VERSION 5.8 ;
BUSBITCHARS "[]" ;
DIVIDERCHAR "/" ;
UNITS
    DATABASE MICRONS 1000 ;
END UNITS

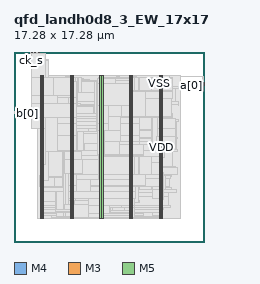
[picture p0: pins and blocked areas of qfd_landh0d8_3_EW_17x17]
MACRO qfd_landh0d8_3_EW_17x17
  FOREIGN qfd_landh0d8_3_EW_17x17 0 0 ;
  CLASS BLOCK ;
  SIZE 17.28 BY 17.28 ;
  PIN a[0]
    DIRECTION INPUT ;
    USE SIGNAL ;
    PORT
      LAYER M4 ;
        RECT  17.196 14.256 17.28 14.28 ;
    END
  END a[0]
  PIN a[1]
    DIRECTION INPUT ;
    USE SIGNAL ;
    PORT
      LAYER M4 ;
        RECT  17.196 14.352 17.28 14.376 ;
    END
  END a[1]
  PIN a[2]
    DIRECTION INPUT ;
    USE SIGNAL ;
    PORT
      LAYER M4 ;
        RECT  17.196 14.448 17.28 14.472 ;
    END
  END a[2]
  PIN b[0]
    DIRECTION OUTPUT ;
    USE SIGNAL ;
    PORT
      LAYER M4 ;
        RECT  0 11.664 0.084 11.688 ;
    END
  END b[0]
  PIN b[1]
    DIRECTION OUTPUT ;
    USE SIGNAL ;
    PORT
      LAYER M4 ;
        RECT  0 11.76 0.084 11.784 ;
    END
  END b[1]
  PIN b[2]
    DIRECTION OUTPUT ;
    USE SIGNAL ;
    PORT
      LAYER M4 ;
        RECT  0 11.856 0.084 11.88 ;
    END
  END b[2]
  PIN ck
    DIRECTION INPUT ;
    USE SIGNAL ;
    PORT
      LAYER M3 ;
        RECT  1.548 17.243 1.566 17.28 ;
    END
  END ck
  PIN ck_s
    DIRECTION INPUT ;
    USE SIGNAL ;
    PORT
      LAYER M3 ;
        RECT  1.62 17.243 1.638 17.28 ;
    END
  END ck_s
  PIN en
    DIRECTION INPUT ;
    USE SIGNAL ;
    PORT
      LAYER M3 ;
        RECT  1.692 17.243 1.71 17.28 ;
    END
  END en
  PIN fault
    DIRECTION OUTPUT ;
    USE SIGNAL ;
    PORT
      LAYER M3 ;
        RECT  1.764 17.243 1.782 17.28 ;
    END
  END fault
  PIN k0
    DIRECTION INPUT ;
    USE SIGNAL ;
    PORT
      LAYER M3 ;
        RECT  1.836 17.243 1.854 17.28 ;
    END
  END k0
  PIN k1
    DIRECTION INPUT ;
    USE SIGNAL ;
    PORT
      LAYER M3 ;
        RECT  1.908 17.243 1.926 17.28 ;
    END
  END k1
  PIN k2
    DIRECTION INPUT ;
    USE SIGNAL ;
    PORT
      LAYER M3 ;
        RECT  1.98 17.243 1.998 17.28 ;
    END
  END k2
  PIN k3
    DIRECTION INPUT ;
    USE SIGNAL ;
    PORT
      LAYER M3 ;
        RECT  2.052 17.243 2.07 17.28 ;
    END
  END k3
  PIN rs
    DIRECTION INPUT ;
    USE SIGNAL ;
    PORT
      LAYER M3 ;
        RECT  2.124 17.243 2.142 17.28 ;
    END
  END rs
  PIN tie_hi
    DIRECTION OUTPUT ;
    USE SIGNAL ;
    PORT
      LAYER M3 ;
        RECT  2.196 17.243 2.214 17.28 ;
    END
  END tie_hi
  PIN tie_lo
    DIRECTION OUTPUT ;
    USE SIGNAL ;
    PORT
      LAYER M3 ;
        RECT  2.268 17.243 2.286 17.28 ;
    END
  END tie_lo
  PIN VDD
    DIRECTION INOUT ;
    USE POWER ;
    PORT
      LAYER M5 ;
        RECT  13.392 2.151 13.512 15.129 ;
        RECT  10.692 2.151 10.812 15.129 ;
        RECT  7.992 2.151 8.112 15.129 ;
        RECT  5.292 2.151 5.412 15.129 ;
        RECT  2.592 2.151 2.712 15.129 ;
    END
  END VDD
  PIN VSS
    DIRECTION INOUT ;
    USE GROUND ;
    PORT
      LAYER M5 ;
        RECT  13.2 2.137 13.32 15.143 ;
        RECT  10.5 2.137 10.62 15.143 ;
        RECT  7.8 2.137 7.92 15.143 ;
        RECT  5.1 2.137 5.22 15.143 ;
        RECT  2.4 2.137 2.52 15.143 ;
    END
  END VSS
  # OT_OBS_CLOSED layer=M5 d_um=1.536 added=34
  OBS
    LAYER RVTN ;
     RECT  2.16 2.16 15.12 2.295 ;
     RECT  2.16 2.565 15.12 2.835 ;
     RECT  2.16 3.105 15.12 3.375 ;
     RECT  2.16 3.645 15.12 3.915 ;
     RECT  2.16 4.185 15.12 4.455 ;
     RECT  2.16 4.725 15.12 4.995 ;
     RECT  2.16 5.265 15.12 5.535 ;
     RECT  2.16 5.805 15.12 6.075 ;
     RECT  2.16 6.345 15.12 6.615 ;
     RECT  2.16 6.885 15.12 7.155 ;
     RECT  2.16 7.425 15.12 7.695 ;
     RECT  2.16 7.965 15.12 8.235 ;
     RECT  2.16 8.505 15.12 8.775 ;
     RECT  2.16 9.045 15.12 9.315 ;
     RECT  2.16 9.585 15.12 9.855 ;
     RECT  2.16 10.125 15.12 10.395 ;
     RECT  2.16 10.665 15.12 10.935 ;
     RECT  2.16 11.205 15.12 11.475 ;
     RECT  2.16 11.745 15.12 12.015 ;
     RECT  2.16 12.285 15.12 12.555 ;
     RECT  2.16 12.825 15.12 13.095 ;
     RECT  2.16 13.365 15.12 13.635 ;
     RECT  2.16 13.905 15.12 14.175 ;
     RECT  2.16 14.445 15.12 14.715 ;
     RECT  2.16 14.985 15.12 15.12 ;
    LAYER RVTP ;
     RECT  2.16 2.295 15.12 2.565 ;
     RECT  2.16 2.835 15.12 3.105 ;
     RECT  2.16 3.375 15.12 3.645 ;
     RECT  2.16 3.915 15.12 4.185 ;
     RECT  2.16 4.455 15.12 4.725 ;
     RECT  2.16 4.995 15.12 5.265 ;
     RECT  2.16 5.535 15.12 5.805 ;
     RECT  2.16 6.075 15.12 6.345 ;
     RECT  2.16 6.615 15.12 6.885 ;
     RECT  2.16 7.155 15.12 7.425 ;
     RECT  2.16 7.695 15.12 7.965 ;
     RECT  2.16 8.235 15.12 8.505 ;
     RECT  2.16 8.775 15.12 9.045 ;
     RECT  2.16 9.315 15.12 9.585 ;
     RECT  2.16 9.855 15.12 10.125 ;
     RECT  2.16 10.395 15.12 10.665 ;
     RECT  2.16 10.935 15.12 11.205 ;
     RECT  2.16 11.475 15.12 11.745 ;
     RECT  2.16 12.015 15.12 12.285 ;
     RECT  2.16 12.555 15.12 12.825 ;
     RECT  2.16 13.095 15.12 13.365 ;
     RECT  2.16 13.635 15.12 13.905 ;
     RECT  2.16 14.175 15.12 14.445 ;
     RECT  2.16 14.715 15.12 14.985 ;
    LAYER M1 ;
     RECT  2.16 2.151 15.12 15.129 ;
    LAYER M2 ;
     RECT  1.471 17.19 1.571 17.208 ;
     RECT  1.831 13.986 2.047 14.004 ;
     RECT  1.903 12.366 2.16 12.384 ;
     RECT  2.047 13.986 2.16 14.544 ;
     RECT  1.687 16.542 2.867 16.632 ;
     RECT  2.867 16.614 3.119 16.632 ;
     RECT  2.16 2.151 15.12 15.129 ;
     RECT  15.12 14.184 16.547 14.238 ;
     RECT  16.547 14.22 16.619 14.238 ;
     RECT  15.12 15.03 17.195 15.048 ;
    LAYER M3 ;
     RECT  7.815 2.143 7.905 2.191 ;
     RECT  5.115 2.143 5.205 2.227 ;
     RECT  8.64 2.191 8.658 2.227 ;
     RECT  10.515 2.143 10.605 2.227 ;
     RECT  13.215 2.143 13.305 2.227 ;
     RECT  6.3 2.227 6.318 2.251 ;
     RECT  7.668 2.191 7.905 2.251 ;
     RECT  6.3 2.251 7.905 2.263 ;
     RECT  8.64 2.227 9.378 2.263 ;
     RECT  10.515 2.227 10.962 2.263 ;
     RECT  6.3 2.263 10.962 2.371 ;
     RECT  11.772 2.251 11.79 2.371 ;
     RECT  2.415 2.143 2.505 2.413 ;
     RECT  3.384 2.227 5.205 2.413 ;
     RECT  12.564 2.227 13.305 2.413 ;
     RECT  2.415 2.413 5.397 2.605 ;
     RECT  6.3 2.371 11.79 2.605 ;
     RECT  2.415 2.605 11.79 2.641 ;
     RECT  12.564 2.413 13.497 2.641 ;
     RECT  2.415 2.641 13.497 2.911 ;
     RECT  2.415 2.911 13.554 3.145 ;
     RECT  2.415 3.145 14.202 3.299 ;
     RECT  2.415 3.299 14.094 4.145 ;
     RECT  10.008 4.145 14.094 4.531 ;
     RECT  10.008 4.531 14.814 4.757 ;
     RECT  10.008 4.757 14.31 4.919 ;
     RECT  2.415 4.145 9.09 4.927 ;
     RECT  10.008 4.919 14.202 4.927 ;
     RECT  2.415 4.927 14.202 4.955 ;
     RECT  2.415 4.955 14.166 5.035 ;
     RECT  2.34 5.035 14.166 5.063 ;
     RECT  4.392 5.063 14.166 5.737 ;
     RECT  4.392 5.737 14.202 5.773 ;
     RECT  2.34 5.063 3.654 5.845 ;
     RECT  4.392 5.773 14.238 5.845 ;
     RECT  2.34 5.845 14.238 5.995 ;
     RECT  2.34 5.995 14.346 6.077 ;
     RECT  2.415 6.077 14.346 6.115 ;
     RECT  2.415 6.115 14.85 6.809 ;
     RECT  2.415 6.809 14.67 6.845 ;
     RECT  2.415 6.845 14.382 8.275 ;
     RECT  2.415 8.275 14.886 8.429 ;
     RECT  2.415 8.429 14.742 8.488 ;
     RECT  9.432 8.488 14.742 8.969 ;
     RECT  9.576 8.969 14.742 9.391 ;
     RECT  9.576 9.391 14.85 9.509 ;
     RECT  2.415 8.488 8.55 9.895 ;
     RECT  2.415 9.895 8.694 10.093 ;
     RECT  9.576 9.509 14.778 10.129 ;
     RECT  2.415 10.093 8.73 10.327 ;
     RECT  9.54 10.129 14.778 10.327 ;
     RECT  2.415 10.327 14.778 10.625 ;
     RECT  9.432 10.625 14.778 10.939 ;
     RECT  2.415 10.625 8.55 10.975 ;
     RECT  9.432 10.939 14.994 11.129 ;
     RECT  9.432 11.129 14.562 11.165 ;
     RECT  2.34 10.975 8.55 11.261 ;
     RECT  2.415 11.261 8.55 11.419 ;
     RECT  9.432 11.165 14.418 11.419 ;
     RECT  2.415 11.419 14.418 11.669 ;
     RECT  0.108 11.851 0.126 11.981 ;
     RECT  2.415 11.669 14.13 12.361 ;
     RECT  1.908 12.361 14.13 12.451 ;
     RECT  1.908 12.451 14.238 12.523 ;
     RECT  14.976 12.451 14.994 12.523 ;
     RECT  1.908 12.523 14.994 12.749 ;
     RECT  1.908 12.749 14.706 13.945 ;
     RECT  1.908 13.945 14.922 13.981 ;
     RECT  1.836 13.981 14.922 14.099 ;
     RECT  16.524 14.179 16.542 14.215 ;
     RECT  16.524 14.215 16.614 14.285 ;
     RECT  16.596 14.285 16.614 14.381 ;
     RECT  1.836 14.099 14.418 14.441 ;
     RECT  1.836 14.441 11.502 14.717 ;
     RECT  1.836 14.717 6.894 14.783 ;
     RECT  12.276 14.441 14.418 14.867 ;
     RECT  4.572 14.783 6.282 14.909 ;
     RECT  12.276 14.867 13.305 14.909 ;
     RECT  1.836 14.783 3.762 14.945 ;
     RECT  4.572 14.909 6.102 14.945 ;
     RECT  7.704 14.717 11.502 14.945 ;
     RECT  12.276 14.909 12.438 14.945 ;
     RECT  14.148 14.867 14.418 14.945 ;
     RECT  5.94 14.945 6.102 14.957 ;
     RECT  9.324 14.945 11.502 14.957 ;
     RECT  1.836 14.945 3.33 14.981 ;
     RECT  5.94 14.957 5.958 14.981 ;
     RECT  7.815 14.945 8.55 14.981 ;
     RECT  9.324 14.957 9.738 14.981 ;
     RECT  12.42 14.945 12.438 14.981 ;
     RECT  4.644 14.945 5.205 15.017 ;
     RECT  9.324 14.981 9.558 15.053 ;
     RECT  17.172 14.443 17.19 15.053 ;
     RECT  10.515 14.957 11.142 15.089 ;
     RECT  14.148 14.945 14.166 15.089 ;
     RECT  5.115 15.017 5.205 15.137 ;
     RECT  7.815 14.981 7.905 15.137 ;
     RECT  10.515 15.089 10.605 15.137 ;
     RECT  13.215 14.909 13.305 15.137 ;
     RECT  1.836 14.981 3.114 16.537 ;
     RECT  1.692 16.537 3.114 16.565 ;
     RECT  1.692 16.565 2.322 16.601 ;
     RECT  3.096 16.565 3.114 16.637 ;
     RECT  1.692 16.601 2.286 17.083 ;
     RECT  1.62 17.083 2.286 17.179 ;
     RECT  1.476 17.179 2.286 17.219 ;
     RECT  1.548 17.219 2.286 17.243 ;
     RECT  1.566 17.243 1.62 17.261 ;
     RECT  1.638 17.243 1.692 17.261 ;
     RECT  1.71 17.243 1.764 17.261 ;
     RECT  1.782 17.243 1.836 17.261 ;
     RECT  1.854 17.243 1.908 17.261 ;
     RECT  1.926 17.243 1.98 17.261 ;
     RECT  1.998 17.243 2.052 17.261 ;
     RECT  2.07 17.243 2.124 17.261 ;
     RECT  2.142 17.243 2.196 17.261 ;
     RECT  2.214 17.243 2.268 17.261 ;
    LAYER M4 ;
     RECT  0.084 11.664 0.097 11.688 ;
     RECT  0.06 11.688 0.097 11.76 ;
     RECT  0.084 11.76 0.097 11.784 ;
     RECT  0.06 11.784 0.097 11.856 ;
     RECT  0.084 11.856 0.097 11.88 ;
     RECT  1.465 17.184 1.609 17.208 ;
     RECT  0.097 11.664 2.149 11.976 ;
     RECT  1.609 17.088 2.195 17.208 ;
     RECT  2.149 11.664 2.293 12.504 ;
     RECT  1.573 10.368 2.329 10.392 ;
     RECT  2.293 11.664 2.329 12.552 ;
     RECT  2.329 6.048 2.408 6.072 ;
     RECT  2.329 10.368 2.408 12.552 ;
     RECT  2.293 14.832 2.408 14.856 ;
     RECT  2.408 2.148 2.512 15.132 ;
     RECT  2.512 2.418 2.704 14.952 ;
     RECT  2.195 17.088 2.867 17.112 ;
     RECT  2.704 5.568 3.125 8.28 ;
     RECT  2.704 10.368 3.587 14.952 ;
     RECT  2.704 3.648 3.74 4.584 ;
     RECT  3.587 10.368 3.773 14.856 ;
     RECT  3.773 10.368 3.805 13.8 ;
     RECT  3.74 2.688 3.841 4.584 ;
     RECT  3.805 9.792 3.971 13.8 ;
     RECT  3.125 5.952 4.417 8.28 ;
     RECT  3.841 2.304 4.489 4.584 ;
     RECT  4.417 5.664 4.489 8.28 ;
     RECT  3.971 9.792 4.549 10.776 ;
     RECT  4.489 2.304 4.669 8.28 ;
     RECT  3.971 12.384 4.981 13.8 ;
     RECT  4.669 2.304 5.108 8.472 ;
     RECT  4.549 9.696 5.108 10.776 ;
     RECT  4.981 11.952 5.108 13.8 ;
     RECT  4.993 14.928 5.108 14.952 ;
     RECT  5.108 2.148 5.212 15.132 ;
     RECT  5.212 2.418 5.404 14.952 ;
     RECT  5.404 11.952 5.609 14.952 ;
     RECT  5.404 2.784 5.645 10.344 ;
     RECT  5.645 2.832 5.699 10.344 ;
     RECT  5.699 2.832 5.753 10.056 ;
     RECT  5.609 12.384 5.753 14.952 ;
     RECT  5.753 13.584 5.897 14.952 ;
     RECT  5.753 12.384 6.041 12.6 ;
     RECT  5.897 13.632 6.113 14.952 ;
     RECT  5.753 3.408 6.365 10.056 ;
     RECT  6.365 3.408 6.437 9 ;
     RECT  6.437 3.408 6.793 5.832 ;
     RECT  6.365 10.032 6.793 10.056 ;
     RECT  6.793 2.928 6.801 5.832 ;
     RECT  6.041 12.384 7.261 12.408 ;
     RECT  7.261 11.664 7.333 12.408 ;
     RECT  6.113 13.632 7.333 14.616 ;
     RECT  7.333 11.664 7.513 14.616 ;
     RECT  6.793 10.032 7.541 10.344 ;
     RECT  7.513 11.664 7.541 14.712 ;
     RECT  7.541 10.032 7.573 14.712 ;
     RECT  6.801 2.256 7.669 5.832 ;
     RECT  6.437 6.912 7.669 9 ;
     RECT  7.669 2.256 7.808 9 ;
     RECT  7.573 10.032 7.808 14.904 ;
     RECT  7.808 2.148 7.912 15.132 ;
     RECT  7.912 2.418 8.104 14.862 ;
     RECT  8.104 2.592 8.243 14.712 ;
     RECT  8.243 2.592 8.741 8.472 ;
     RECT  8.741 2.832 8.915 8.472 ;
     RECT  8.915 4.512 9.107 8.472 ;
     RECT  8.243 9.984 9.205 14.712 ;
     RECT  9.107 4.656 9.565 8.472 ;
     RECT  9.205 9.984 9.565 14.856 ;
     RECT  9.565 4.656 9.925 14.856 ;
     RECT  8.915 2.832 10.033 3.144 ;
     RECT  10.033 2.832 10.069 3.672 ;
     RECT  9.925 4.656 10.069 14.952 ;
     RECT  10.069 2.832 10.508 14.952 ;
     RECT  10.508 2.148 10.612 15.132 ;
     RECT  10.612 2.256 10.931 14.952 ;
     RECT  10.931 3.552 11.297 14.952 ;
     RECT  11.297 3.552 11.405 3.816 ;
     RECT  11.297 4.8 11.449 14.952 ;
     RECT  11.449 4.8 12.517 9.096 ;
     RECT  11.449 10.272 12.517 14.952 ;
     RECT  12.517 4.8 12.572 14.952 ;
     RECT  10.931 2.256 13.208 2.28 ;
     RECT  12.572 3.936 13.208 14.952 ;
     RECT  13.208 2.148 13.312 15.132 ;
     RECT  13.312 2.418 13.504 14.862 ;
     RECT  13.504 3.84 13.565 6.312 ;
     RECT  13.565 3.84 13.619 6.024 ;
     RECT  13.504 7.728 13.673 13.128 ;
     RECT  13.619 4.752 13.745 6.024 ;
     RECT  13.745 5.136 13.781 6.024 ;
     RECT  13.673 8.4 13.804 13.128 ;
     RECT  13.804 8.448 13.961 13.128 ;
     RECT  13.961 8.496 14.141 13.128 ;
     RECT  13.781 5.76 14.213 6.024 ;
     RECT  14.141 10.176 14.243 13.128 ;
     RECT  13.504 14.256 14.249 14.856 ;
     RECT  14.243 11.184 14.285 13.128 ;
     RECT  14.285 11.184 14.291 13.08 ;
     RECT  14.291 12.528 14.329 13.08 ;
     RECT  14.213 6 14.357 6.024 ;
     RECT  14.329 13.056 14.387 13.08 ;
     RECT  14.249 14.832 14.429 14.856 ;
     RECT  14.141 8.496 14.723 8.52 ;
     RECT  14.291 11.184 14.723 11.208 ;
     RECT  16.513 14.256 16.585 14.28 ;
     RECT  16.585 14.256 17.161 14.376 ;
     RECT  17.161 14.256 17.196 14.28 ;
     RECT  17.161 14.28 17.244 14.352 ;
     RECT  17.161 14.352 17.196 14.376 ;
     RECT  17.161 14.376 17.244 14.448 ;
     RECT  17.161 14.448 17.196 14.472 ;
    LAYER M5 ;
     RECT  2.4 2.137 2.52 2.151 ;
     RECT  5.1 2.137 5.22 2.151 ;
     RECT  7.8 2.137 7.92 2.151 ;
     RECT  10.5 2.137 10.62 2.151 ;
     RECT  13.2 2.137 13.32 2.151 ;
     RECT  7.8 2.151 8.112 2.245 ;
     RECT  10.5 2.151 10.812 2.245 ;
     RECT  6.816 2.245 8.112 2.629 ;
     RECT  3.792 2.677 3.816 2.773 ;
     RECT  5.1 2.151 5.412 2.773 ;
     RECT  3.792 2.773 5.412 2.915 ;
     RECT  10.5 2.245 10.92 3.109 ;
     RECT  6.816 2.629 8.664 3.349 ;
     RECT  9.792 3.109 10.92 3.349 ;
     RECT  4.56 2.915 5.412 3.397 ;
     RECT  4.56 3.397 5.544 3.443 ;
     RECT  4.992 3.443 5.544 3.781 ;
     RECT  13.2 2.151 13.512 3.829 ;
     RECT  4.992 3.781 5.592 3.925 ;
     RECT  6.816 3.349 10.92 3.925 ;
     RECT  13.2 3.829 13.608 3.925 ;
     RECT  4.992 3.925 11.064 4.595 ;
     RECT  12.624 3.925 13.608 4.787 ;
     RECT  6.96 4.595 11.064 5.029 ;
     RECT  4.992 4.595 5.64 5.171 ;
     RECT  6.96 5.029 11.976 5.171 ;
     RECT  13.2 4.787 13.608 5.171 ;
     RECT  6.96 5.171 10.812 5.699 ;
     RECT  11.952 5.171 11.976 5.749 ;
     RECT  13.2 5.171 13.512 5.749 ;
     RECT  7.68 5.699 10.812 6.133 ;
     RECT  11.952 5.749 13.512 6.179 ;
     RECT  5.1 5.171 5.64 6.181 ;
     RECT  5.1 6.181 6.264 6.229 ;
     RECT  2.4 2.151 2.712 7.093 ;
     RECT  12.528 6.179 13.512 7.187 ;
     RECT  4.56 6.229 6.264 7.475 ;
     RECT  7.68 6.133 10.92 7.765 ;
     RECT  7.68 7.765 11.736 7.861 ;
     RECT  7.632 7.861 11.736 8.003 ;
     RECT  4.56 7.475 6.168 8.245 ;
     RECT  3.936 8.245 6.168 8.291 ;
     RECT  13.2 7.187 13.512 8.293 ;
     RECT  12.96 8.293 13.512 8.389 ;
     RECT  12.96 8.389 13.752 8.485 ;
     RECT  9.6 8.003 11.736 8.867 ;
     RECT  9.6 8.867 11.4 9.155 ;
     RECT  12.96 8.485 14.712 9.587 ;
     RECT  3.936 8.291 5.688 9.731 ;
     RECT  9.648 9.155 11.4 9.731 ;
     RECT  7.632 8.003 8.232 10.165 ;
     RECT  13.056 9.587 14.712 10.307 ;
     RECT  2.4 7.093 2.856 10.357 ;
     RECT  3.936 9.731 3.96 10.741 ;
     RECT  5.1 9.731 5.688 10.741 ;
     RECT  9.648 9.731 10.812 10.741 ;
     RECT  7.632 10.165 8.616 10.789 ;
     RECT  13.2 10.307 14.712 11.219 ;
     RECT  1.584 10.357 2.856 11.317 ;
     RECT  3.936 10.741 5.688 11.317 ;
     RECT  9.648 10.741 11.4 11.365 ;
     RECT  13.2 11.219 14.28 11.365 ;
     RECT  9.648 11.365 14.28 11.459 ;
     RECT  7.584 10.789 8.616 12.421 ;
     RECT  9.744 11.459 10.812 12.421 ;
     RECT  1.584 11.317 5.688 12.611 ;
     RECT  11.952 11.459 14.28 13.045 ;
     RECT  4.992 12.611 5.688 13.139 ;
     RECT  1.584 12.611 3.96 13.331 ;
     RECT  11.952 13.045 14.376 13.667 ;
     RECT  12.144 13.667 14.376 13.763 ;
     RECT  7.584 12.421 10.812 14.435 ;
     RECT  5.1 13.139 5.688 14.627 ;
     RECT  9.216 14.435 10.812 14.723 ;
     RECT  9.216 14.723 9.24 14.867 ;
     RECT  12.48 13.763 14.376 14.867 ;
     RECT  7.584 14.435 8.112 14.915 ;
     RECT  1.584 13.331 3.576 14.963 ;
     RECT  12.48 14.867 13.512 14.963 ;
     RECT  5.1 14.627 5.412 15.129 ;
     RECT  7.8 14.915 8.112 15.129 ;
     RECT  10.5 14.723 10.812 15.129 ;
     RECT  13.2 14.963 13.512 15.129 ;
     RECT  5.1 15.129 5.22 15.143 ;
     RECT  7.8 15.129 7.92 15.143 ;
     RECT  10.5 15.129 10.62 15.143 ;
     RECT  13.2 15.129 13.32 15.143 ;
     RECT  1.584 14.963 2.856 17.123 ;
     RECT  1.584 17.123 2.184 17.219 ;
     RECT  5.412 2.245 6.816 3.397 ;
     RECT  2.712 2.677 3.792 2.915 ;
     RECT  3.816 2.677 5.1 2.773 ;
     RECT  8.664 3.109 9.792 3.349 ;
     RECT  5.544 3.397 6.816 3.781 ;
     RECT  5.592 3.781 6.816 3.925 ;
     RECT  5.64 4.595 6.96 5.699 ;
     RECT  12.624 4.787 13.2 5.029 ;
     RECT  11.976 5.029 13.2 5.749 ;
     RECT  4.992 5.171 5.1 6.229 ;
     RECT  10.812 5.171 11.952 6.133 ;
     RECT  5.64 5.699 7.68 6.181 ;
     RECT  10.92 6.133 11.952 6.179 ;
     RECT  6.264 6.181 7.68 7.475 ;
     RECT  12.528 7.187 13.2 7.765 ;
     RECT  6.168 7.475 7.68 7.861 ;
     RECT  11.736 7.765 13.2 8.293 ;
     RECT  6.168 7.861 7.632 8.291 ;
     RECT  8.232 8.003 9.6 9.155 ;
     RECT  2.856 8.245 3.936 11.317 ;
     RECT  11.736 8.293 12.96 8.867 ;
     RECT  8.232 9.155 9.648 10.165 ;
     RECT  3.96 9.731 5.1 10.741 ;
     RECT  10.812 9.731 11.4 10.741 ;
     RECT  8.616 10.165 9.648 11.459 ;
     RECT  13.056 10.307 13.2 11.365 ;
     RECT  8.616 11.459 9.744 12.421 ;
     RECT  10.812 11.459 11.952 13.667 ;
     RECT  3.96 12.611 4.992 13.139 ;
     RECT  3.96 13.139 5.1 13.331 ;
     RECT  3.576 13.331 5.1 14.963 ;
     RECT  10.812 13.667 12.144 13.763 ;
     RECT  8.112 14.435 9.216 14.867 ;
     RECT  9.24 14.723 10.5 14.867 ;
  END
END qfd_landh0d8_3_EW_17x17
END LIBRARY
